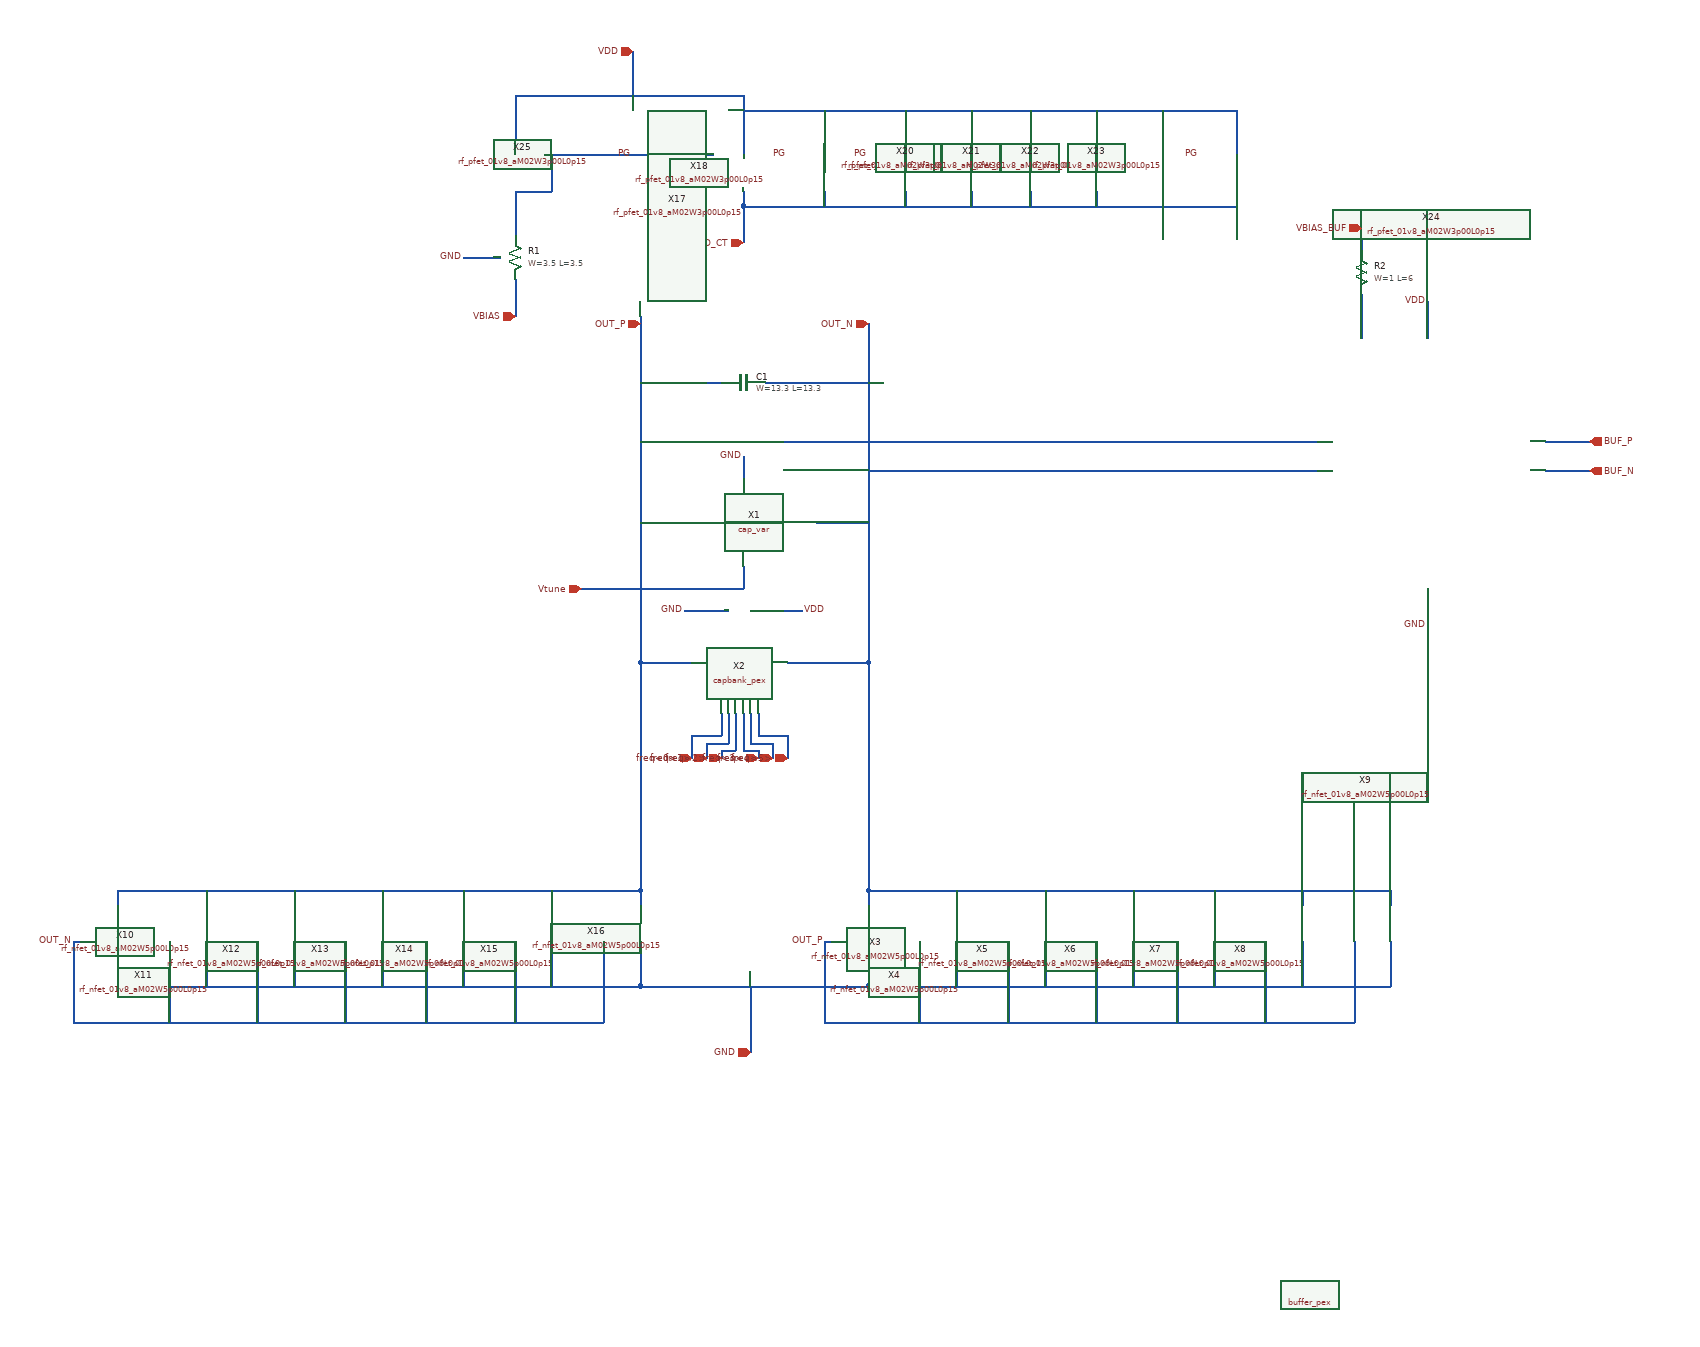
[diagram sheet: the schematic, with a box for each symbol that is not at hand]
v {xschem version=3.0.0 file_version=1.2 }
G {}
K {}
V {}
S {}
E {}
N 290 -420 360 -420 {
lab=OUT_P}
N 290 -820 290 -420 {
lab=OUT_P}
N 290 -800 400 -800 {
lab=OUT_P}
N 290 -610 330 -610 {
lab=OUT_P}
N 490 -420 600 -420 {
lab=OUT_N}
N 600 -820 600 -420 {
lab=OUT_N}
N 460 -800 600 -800 {
lab=OUT_N}
N 530 -610 600 -610 {
lab=OUT_N}
N 290 -890 290 -820 {
lab=OUT_P}
N 600 -880 600 -820 {
lab=OUT_N}
N 430 -550 430 -520 {
lab=Vtune}
N 210 -520 430 -520 {
lab=Vtune}
N 430 -700 430 -670 {
lab=GND}
N 160 -1110 390 -1110 {
lab=PG}
N 120 -1190 120 -1140 {
lab=VDD}
N 120 -1190 430 -1190 {
lab=VDD}
N 430 -1190 430 -1140 {
lab=VDD}
N 120 -1140 120 -1110 {
lab=VDD}
N 120 -1060 170 -1060 {
lab=PG}
N 170 -1110 170 -1060 {
lab=PG}
N 120 -940 120 -890 {
lab=VBIAS}
N 50 -970 100 -970 {
lab=GND}
N 430 -1140 430 -1110 {
lab=VDD}
N 1100 -1170 1100 -1110 {
lab=VDD}
N 1000 -1170 1000 -1110 {
lab=VDD}
N 910 -1170 910 -1110 {
lab=VDD}
N 820 -1170 820 -1110 {
lab=VDD}
N 740 -1170 740 -1110 {
lab=VDD}
N 650 -1170 650 -1110 {
lab=VDD}
N 540 -1170 540 -1110 {
lab=VDD}
N 430 -1170 1100 -1170 {
lab=VDD}
N 430 -1040 1100 -1040 {
lab=IND_CT}
N 430 -1040 430 -990 {
lab=IND_CT}
N 400 -350 400 -320 {
lab=freq<0>}
N 410 -350 410 -320 {
lab=freq<1>}
N 420 -350 420 -320 {
lab=freq<2>}
N 430 -350 430 -320 {
lab=freq<3>}
N 440 -350 440 -320 {
lab=freq<4>}
N 450 -350 450 -320 {
lab=freq<5>}
N 370 -320 400 -320 {
lab=freq<0>}
N 410 -320 410 -310 {
lab=freq<1>}
N 390 -310 410 -310 {
lab=freq<1>}
N 420 -320 420 -300 {
lab=freq<2>}
N 430 -320 430 -310 {
lab=freq<3>}
N 450 -320 490 -320 {
lab=freq<5>}
N 490 -320 490 -300 {
lab=freq<5>}
N 440 -320 440 -310 {
lab=freq<4>}
N 440 -310 470 -310 {
lab=freq<4>}
N 470 -310 470 -300 {
lab=freq<4>}
N 430 -310 430 -300 {
lab=freq<3>}
N 430 -300 450 -300 {
lab=freq<3>}
N 450 -300 450 -290 {
lab=freq<3>}
N 470 -300 470 -290 {
lab=freq<4>}
N 490 -300 490 -290 {
lab=freq<5>}
N 400 -300 420 -300 {
lab=freq<2>}
N 400 -300 400 -290 {
lab=freq<2>}
N 380 -310 390 -310 {
lab=freq<1>}
N 380 -310 380 -290 {
lab=freq<1>}
N 360 -320 370 -320 {
lab=freq<0>}
N 360 -320 360 -290 {
lab=freq<0>}
N 350 -490 410 -490 {
lab=GND}
N 440 -490 510 -490 {
lab=VDD}
N 280 -1250 280 -1190 {
lab=VDD}
N 600 -40 600 -10 {
lab=GND}
N 600 -10 600 20 {
lab=GND}
N 720 -40 720 -10 {
lab=GND}
N 720 -10 720 20 {
lab=GND}
N 840 -40 840 -10 {
lab=GND}
N 840 -10 840 20 {
lab=GND}
N 960 -40 960 -10 {
lab=GND}
N 960 -10 960 20 {
lab=GND}
N 1070 -40 1070 -10 {
lab=GND}
N 1070 -10 1070 20 {
lab=GND}
N 1190 -40 1190 -10 {
lab=GND}
N 1190 -10 1190 20 {
lab=GND}
N 1310 -40 1310 -10 {
lab=GND}
N 1310 -10 1310 20 {
lab=GND}
N 600 20 1310 20 {
lab=GND}
N 600 -110 1310 -110 {
lab=OUT_N}
N 600 -420 600 -120 {
lab=OUT_N}
N 600 -120 600 -110 {
lab=OUT_N}
N -420 -40 -420 -10 {
lab=GND}
N -420 -10 -420 20 {
lab=GND}
N -300 -40 -300 -10 {
lab=GND}
N -300 -10 -300 20 {
lab=GND}
N -180 -40 -180 -10 {
lab=GND}
N -180 -10 -180 20 {
lab=GND}
N -60 -40 -60 -10 {
lab=GND}
N -60 -10 -60 20 {
lab=GND}
N 50 -40 50 -10 {
lab=GND}
N 50 -10 50 20 {
lab=GND}
N 170 -40 170 -10 {
lab=GND}
N 170 -10 170 20 {
lab=GND}
N 290 -40 290 -10 {
lab=GND}
N 290 -10 290 20 {
lab=GND}
N -420 20 290 20 {
lab=GND}
N -420 -110 290 -110 {
lab=OUT_P}
N 290 -420 290 -110 {
lab=OUT_P}
N 290 20 600 20 {
lab=GND}
N 440 20 440 110 {
lab=GND}
N 120 -1060 120 -1000 {
lab=PG}
N 540 -1060 540 -1040 {
lab=IND_CT}
N 430 -1060 430 -1040 {
lab=IND_CT}
N 1100 -1060 1100 -1040 {
lab=IND_CT}
N 1000 -1060 1000 -1040 {
lab=IND_CT}
N 910 -1060 910 -1040 {
lab=IND_CT}
N 820 -1060 820 -1040 {
lab=IND_CT}
N 740 -1060 740 -1040 {
lab=IND_CT}
N 650 -1060 650 -1040 {
lab=IND_CT}
N -420 -110 -420 -90 {
lab=OUT_P}
N -480 -40 -470 -40 {
lab=OUT_N}
N -300 -110 -300 -90 {
lab=OUT_P}
N -180 -110 -180 -90 {
lab=OUT_P}
N -350 -40 -350 70 {
lab=OUT_N}
N -230 -40 -230 70 {
lab=OUT_N}
N -110 -40 -110 70 {
lab=OUT_N}
N -60 -110 -60 -90 {
lab=OUT_P}
N 290 -110 290 -90 {
lab=OUT_P}
N 170 -110 170 -90 {
lab=OUT_P}
N 50 -110 50 -90 {
lab=OUT_P}
N -0 -40 -0 70 {
lab=OUT_N}
N 120 -40 120 70 {
lab=OUT_N}
N 240 -40 240 70 {
lab=OUT_N}
N -480 70 240 70 {
lab=OUT_N}
N -480 -40 -480 70 {
lab=OUT_N}
N 540 -40 550 -40 {
lab=OUT_P}
N 600 -110 600 -90 {
lab=OUT_N}
N 720 -110 720 -90 {
lab=OUT_N}
N 840 -110 840 -90 {
lab=OUT_N}
N 960 -110 960 -90 {
lab=OUT_N}
N 1070 -110 1070 -90 {
lab=OUT_N}
N 1190 -110 1190 -90 {
lab=OUT_N}
N 1310 -110 1310 -90 {
lab=OUT_N}
N 1260 -40 1260 70 {
lab=OUT_P}
N 1140 -40 1140 70 {
lab=OUT_P}
N 1020 -40 1020 70 {
lab=OUT_P}
N 910 -40 910 70 {
lab=OUT_P}
N 790 -40 790 70 {
lab=OUT_P}
N 670 -40 670 70 {
lab=OUT_P}
N 540 -40 540 70 {
lab=OUT_P}
N 540 70 1260 70 {
lab=OUT_P}
N 1360 -910 1360 -860 {
lab=VDD}
N 1360 -520 1360 -470 {
lab=GND}
N 290 -720 900 -720 {
lab=OUT_P}
N 600 -680 900 -680 {
lab=OUT_N}
N 900 -720 1210 -720 {
lab=OUT_P}
N 900 -680 1210 -680 {
lab=OUT_N}
N 1520 -720 1580 -720 {
lab=BUF_P}
N 1520 -680 1580 -680 {
lab=BUF_N}
N 1270 -920 1270 -860 {
lab=#net1}
N 1270 -1010 1270 -980 {
lab=VBIAS_BUF}
C {cap_var.sym} 330 -550 0 0 {name=X1}
C {sky130_fd_pr/cap_mim_m3_1.sym} 430 -800 3 0 {name=C1 model=cap_mim_m3_1 W=13.3 L=13.3 MF=1 spiceprefix=X}
C {devices/iopin.sym} 290 -880 3 0 {name=p1 lab=OUT_P}
C {devices/lab_pin.sym} 430 -700 0 0 {name=l1 sig_type=std_logic lab=GND}
C {sky130_fd_pr/res_high_po.sym} 120 -970 0 0 {name=R1
W=3.5
L=3.5
model=res_high_po
spiceprefix=X
mult=1}
C {devices/lab_pin.sym} 50 -970 0 0 {name=l2 sig_type=std_logic lab=GND}
C {devices/lab_pin.sym} 280 -1110 3 0 {name=l3 sig_type=std_logic lab=PG}
C {devices/lab_pin.sym} 490 -1110 3 0 {name=l4 sig_type=std_logic lab=PG}
C {devices/lab_pin.sym} 600 -1110 3 0 {name=l5 sig_type=std_logic lab=PG}
C {devices/lab_pin.sym} 690 -1110 3 0 {name=l6 sig_type=std_logic lab=PG}
C {devices/lab_pin.sym} 770 -1110 3 0 {name=l7 sig_type=std_logic lab=PG}
C {devices/lab_pin.sym} 860 -1110 3 0 {name=l8 sig_type=std_logic lab=PG}
C {devices/lab_pin.sym} 950 -1110 3 0 {name=l9 sig_type=std_logic lab=PG}
C {devices/lab_pin.sym} 1050 -1110 3 0 {name=l10 sig_type=std_logic lab=PG}
C {devices/iopin.sym} 430 -990 1 0 {name=p3 lab=IND_CT}
C {devices/iopin.sym} 120 -890 1 0 {name=p4 lab=VBIAS}
C {devices/iopin.sym} 210 -520 2 0 {name=p5 lab=Vtune}
C {devices/ipin.sym} 360 -290 3 0 {name=p7 lab=freq\\<0\\>}
C {devices/ipin.sym} 380 -290 3 0 {name=p6 lab=freq\\<1\\>}
C {devices/ipin.sym} 400 -290 3 0 {name=p8 lab=freq\\<2\\>}
C {devices/ipin.sym} 450 -290 3 0 {name=p9 lab=freq\\<3\\>}
C {devices/ipin.sym} 470 -290 3 0 {name=p10 lab=freq\\<4\\>}
C {devices/ipin.sym} 490 -290 3 0 {name=p11 lab=freq\\<5\\>}
C {devices/lab_pin.sym} 350 -490 0 0 {name=l11 sig_type=std_logic lab=GND}
C {devices/lab_pin.sym} 510 -490 2 0 {name=l12 sig_type=std_logic lab=VDD}
C {devices/iopin.sym} 280 -1250 3 0 {name=p12 lab=VDD}
C {rf_nfet_01v8_aM02W5p00L0p15.sym} 530 30 0 0 {name=X3}
C {devices/lab_pin.sym} 540 -40 0 0 {name=l13 sig_type=std_logic lab=OUT_P}
C {rf_nfet_01v8_aM02W5p00L0p15.sym} 650 30 0 0 {name=X4}
C {rf_nfet_01v8_aM02W5p00L0p15.sym} 770 30 0 0 {name=X5}
C {rf_nfet_01v8_aM02W5p00L0p15.sym} 890 30 0 0 {name=X6}
C {rf_nfet_01v8_aM02W5p00L0p15.sym} 1000 30 0 0 {name=X7}
C {rf_nfet_01v8_aM02W5p00L0p15.sym} 1120 30 0 0 {name=X8}
C {rf_nfet_01v8_aM02W5p00L0p15.sym} 1240 30 0 0 {name=X9}
C {rf_nfet_01v8_aM02W5p00L0p15.sym} -490 30 0 0 {name=X10}
C {devices/lab_pin.sym} -480 -40 0 0 {name=l20 sig_type=std_logic lab=OUT_N}
C {rf_nfet_01v8_aM02W5p00L0p15.sym} -370 30 0 0 {name=X11}
C {rf_nfet_01v8_aM02W5p00L0p15.sym} -250 30 0 0 {name=X12}
C {rf_nfet_01v8_aM02W5p00L0p15.sym} -130 30 0 0 {name=X13}
C {rf_nfet_01v8_aM02W5p00L0p15.sym} -20 30 0 0 {name=X14}
C {rf_nfet_01v8_aM02W5p00L0p15.sym} 100 30 0 0 {name=X15}
C {rf_nfet_01v8_aM02W5p00L0p15.sym} 220 30 0 0 {name=X16}
C {devices/iopin.sym} 440 110 1 0 {name=p13 lab=GND}
C {rf_pfet_01v8_aM02W3p00L0p15.sym} 190 -1040 0 1 {name=X25}
C {rf_pfet_01v8_aM02W3p00L0p15.sym} 360 -1040 0 0 {name=X17}
C {rf_pfet_01v8_aM02W3p00L0p15.sym} 470 -1040 0 0 {name=X18}
C {rf_pfet_01v8_aM02W3p00L0p15.sym} 580 -1040 0 0 {name=X19}
C {rf_pfet_01v8_aM02W3p00L0p15.sym} 670 -1040 0 0 {name=X20}
C {rf_pfet_01v8_aM02W3p00L0p15.sym} 750 -1040 0 0 {name=X21}
C {rf_pfet_01v8_aM02W3p00L0p15.sym} 840 -1040 0 0 {name=X22}
C {rf_pfet_01v8_aM02W3p00L0p15.sym} 930 -1040 0 0 {name=X23}
C {rf_pfet_01v8_aM02W3p00L0p15.sym} 1030 -1040 0 0 {name=X24}
C {devices/lab_pin.sym} 1360 -910 1 0 {name=l23 sig_type=std_logic lab=VDD}
C {devices/lab_pin.sym} 1360 -470 3 0 {name=l24 sig_type=std_logic lab=GND}
C {devices/opin.sym} 1580 -720 0 0 {name=p14 lab=BUF_P}
C {devices/opin.sym} 1580 -680 0 0 {name=p15 lab=BUF_N}
C {devices/iopin.sym} 600 -880 3 0 {name=p16 lab=OUT_N}
C {devices/iopin.sym} 1270 -1010 3 0 {name=p17 lab=VBIAS_BUF}
C {sky130_fd_pr/res_generic_po.sym} 1270 -950 0 0 {name=R2
W=1
L=6
model=res_generic_po
mult=1}
C {capbank_pex.sym} 360 -350 0 0 {name=X2}
C {buffer_pex.sym} 1200 440 0 0 {}
